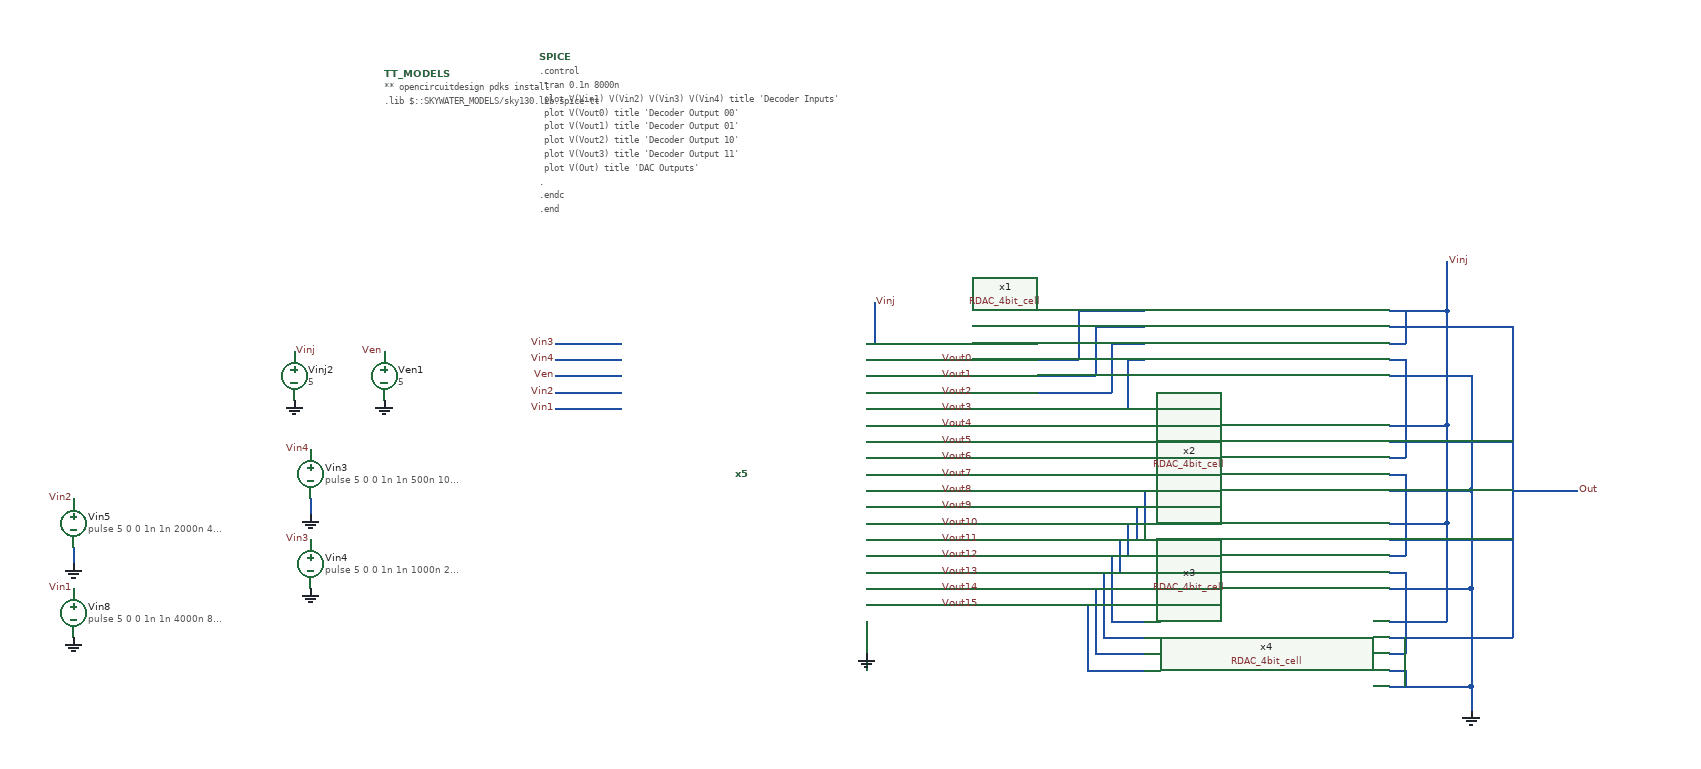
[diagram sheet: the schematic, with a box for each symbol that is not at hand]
v {xschem version=3.4.5 file_version=1.2
}
G {}
K {}
V {}
S {}
E {}
N 340 -380 400 -380 {
lab=Vout4}
N 340 -360 400 -360 {
lab=Vout5}
N 340 -340 400 -340 {
lab=Vout6}
N 340 -320 400 -320 {
lab=Vout7}
N 340 -300 400 -300 {
lab=Vout8}
N 340 -280 400 -280 {
lab=Vout9}
N 400 -520 400 -460 {
lab=Vout0}
N 400 -520 480 -520 {
lab=Vout0}
N 420 -500 480 -500 {
lab=Vout1}
N 420 -500 420 -440 {
lab=Vout1}
N 400 -440 420 -440 {
lab=Vout1}
N 400 -420 440 -420 {
lab=Vout2}
N 440 -480 440 -420 {
lab=Vout2}
N 440 -480 480 -480 {
lab=Vout2}
N 400 -400 460 -400 {
lab=Vout3}
N 460 -460 460 -400 {
lab=Vout3}
N 460 -460 480 -460 {
lab=Vout3}
N 400 -380 480 -380 {
lab=Vout4}
N 400 -360 480 -360 {
lab=Vout5}
N 400 -340 480 -340 {
lab=Vout6}
N 400 -320 480 -320 {
lab=Vout7}
N 400 -300 480 -300 {
lab=Vout8}
N 480 -300 480 -260 {
lab=Vout8}
N 400 -280 470 -280 {
lab=Vout9}
N 470 -280 470 -240 {
lab=Vout9}
N 470 -240 480 -240 {
lab=Vout9}
N 340 -260 460 -260 {
lab=Vout10}
N 460 -260 460 -220 {
lab=Vout10}
N 460 -220 480 -220 {
lab=Vout10}
N 340 -240 450 -240 {
lab=Vout11}
N 450 -240 450 -200 {
lab=Vout11}
N 450 -200 480 -200 {
lab=Vout11}
N 340 -220 440 -220 {
lab=Vout12}
N 440 -220 440 -140 {
lab=Vout12}
N 440 -140 480 -140 {
lab=Vout12}
N 430 -120 480 -120 {
lab=Vout13}
N 430 -200 430 -120 {
lab=Vout13}
N 340 -200 430 -200 {
lab=Vout13}
N 340 -180 420 -180 {
lab=Vout14}
N 420 -180 420 -100 {
lab=Vout14}
N 420 -100 480 -100 {
lab=Vout14}
N 410 -80 480 -80 {
lab=Vout15}
N 410 -160 410 -80 {
lab=Vout15}
N 340 -160 410 -160 {
lab=Vout15}
N 780 -520 850 -520 {
lab=Vinj}
N 850 -520 850 -380 {
lab=Vinj}
N 780 -380 850 -380 {
lab=Vinj}
N 850 -380 850 -260 {
lab=Vinj}
N 780 -260 850 -260 {
lab=Vinj}
N 780 -140 850 -140 {
lab=Vinj}
N 850 -260 850 -140 {
lab=Vinj}
N 780 -60 880 -60 {
lab=GND}
N 880 -180 880 -60 {
lab=GND}
N 780 -180 880 -180 {
lab=GND}
N 780 -300 880 -300 {
lab=GND}
N 780 -440 880 -440 {
lab=GND}
N 880 -300 880 -180 {
lab=GND}
N 880 -440 880 -300 {
lab=GND}
N 780 -500 930 -500 {
lab=Out}
N 930 -500 930 -120 {
lab=Out}
N 780 -120 930 -120 {
lab=Out}
N 780 -240 930 -240 {
lab=Out}
N 780 -360 930 -360 {
lab=Out}
N 930 -300 1010 -300 {
lab=Out}
N 780 -480 800 -480 {
lab=Vinj}
N 800 -520 800 -480 {
lab=Vinj}
N 850 -580 850 -520 {
lab=Vinj}
N 780 -460 800 -460 {
lab=#net1}
N 800 -460 800 -340 {
lab=#net1}
N 780 -340 800 -340 {
lab=#net1}
N 780 -320 800 -320 {
lab=#net2}
N 800 -320 800 -220 {
lab=#net2}
N 780 -220 800 -220 {
lab=#net2}
N 780 -200 800 -200 {
lab=#net3}
N 800 -200 800 -100 {
lab=#net3}
N 780 -100 800 -100 {
lab=#net3}
N 780 -80 800 -80 {
lab=GND}
N 800 -80 800 -60 {
lab=GND}
N 880 -60 880 -30 {
lab=GND}
N -540 -290 -540 -270 {
lab=GND}
N -220 -400 -160 -400 {
lab=Vin1}
N -240 -420 -160 -420 {
lab=Vin2}
N -240 -440 -160 -440 {
lab=Ven}
N -240 -400 -220 -400 {
lab=Vin1}
N -830 -230 -830 -210 {
lab=GND}
N -240 -480 -160 -480 {
lab=Vin3}
N -240 -460 -160 -460 {
lab=Vin4}
N 140 -120 140 -100 {
lab=GND}
N 140 -460 230 -460 {
lab=Vout0}
N 140 -440 230 -440 {
lab=Vout1}
N 140 -420 230 -420 {
lab=Vout2}
N 140 -400 230 -400 {
lab=Vout3}
N 140 -380 230 -380 {
lab=Vout4}
N 140 -360 230 -360 {
lab=Vout5}
N 140 -340 230 -340 {
lab=Vout6}
N 140 -320 230 -320 {
lab=Vout7}
N 140 -300 230 -300 {
lab=Vout8}
N 140 -280 230 -280 {
lab=Vout9}
N 140 -260 230 -260 {
lab=Vout10}
N 140 -240 230 -240 {
lab=Vout11}
N 140 -220 230 -220 {
lab=Vout12}
N 140 -200 230 -200 {
lab=Vout13}
N 140 -180 230 -180 {
lab=Vout14}
N 140 -160 230 -160 {
lab=Vout15}
N 140 -140 140 -120 {
lab=GND}
N 140 -480 150 -480 {
lab=Vinj}
N 150 -530 150 -480 {
lab=Vinj}
N 230 -460 400 -460 {
lab=Vout0}
N 230 -440 400 -440 {
lab=Vout1}
N 230 -420 400 -420 {
lab=Vout2}
N 230 -400 400 -400 {
lab=Vout3}
N 230 -380 340 -380 {
lab=Vout4}
N 230 -360 340 -360 {
lab=Vout5}
N 230 -340 340 -340 {
lab=Vout6}
N 230 -320 340 -320 {
lab=Vout7}
N 230 -300 340 -300 {
lab=Vout8}
N 230 -280 340 -280 {
lab=Vout9}
N 230 -260 340 -260 {
lab=Vout10}
N 230 -240 340 -240 {
lab=Vout11}
N 230 -220 340 -220 {
lab=Vout12}
N 230 -200 340 -200 {
lab=Vout13}
N 230 -180 340 -180 {
lab=Vout14}
N 230 -160 340 -160 {
lab=Vout15}
C {devices/code.sym} -450 -810 0 0 {name=TT_MODELS
only_toplevel=true
format="tcleval( @value )"
value="
** opencircuitdesign pdks install
.lib $::SKYWATER_MODELS/sky130.lib.spice tt

"
spice_ignore=false}
C {code_shown.sym} -260 -830 0 0 {name=SPICE only_toplevel=false value="
.control
	tran 0.1n 8000n
	plot V(Vin1) V(Vin2) V(Vin3) V(Vin4) title 'Decoder Inputs'
	plot V(Vout0) title 'Decoder Output 00'
	plot V(Vout1) title 'Decoder Output 01'
	plot V(Vout2) title 'Decoder Output 10'
	plot V(Vout3) title 'Decoder Output 11'
	plot V(Out) title 'DAC Outputs'
	
.
.endc

.end"}
C {RDAC_4bit_cell.sym} 630 -480 0 0 {name=x1}
C {RDAC_4bit_cell.sym} 630 -340 0 0 {name=x2}
C {RDAC_4bit_cell.sym} 630 -220 0 0 {name=x3}
C {RDAC_4bit_cell.sym} 630 -100 0 0 {name=x4}
C {gnd.sym} 880 -30 0 0 {name=l7 lab=GND}
C {lab_pin.sym} 850 -580 2 0 {name=p1 sig_type=std_logic lab=Vinj}
C {lab_pin.sym} 1010 -300 2 0 {name=p14 sig_type=std_logic lab=Out}
C {vsource.sym} -540 -320 0 0 {name=Vin3 value="pulse 5 0 0 1n 1n 500n 1000n" savecurrent=false}
C {gnd.sym} -540 -270 0 0 {name=l1 lab=GND}
C {vsource.sym} -540 -210 0 0 {name=Vin4 value="pulse 5 0 0 1n 1n 1000n 2000n" savecurrent=false}
C {gnd.sym} -540 -180 0 0 {name=l5 lab=GND}
C {vsource.sym} -560 -440 0 0 {name=Vinj2 value=5 savecurrent=false}
C {gnd.sym} -560 -410 0 0 {name=Vinj3 lab=GND
value=5}
C {lab_pin.sym} -560 -470 2 0 {name=p2 sig_type=std_logic lab=Vinj}
C {lab_pin.sym} -830 -180 0 0 {name=p3 sig_type=std_logic lab=Vin1}
C {lab_pin.sym} -830 -290 0 0 {name=p4 sig_type=std_logic lab=Vin2}
C {vsource.sym} -450 -440 0 0 {name=Ven1 value=5 savecurrent=false}
C {gnd.sym} -450 -410 0 0 {name=l6 lab=GND}
C {lab_pin.sym} -450 -470 0 0 {name=p5 sig_type=std_logic lab=Ven}
C {lab_pin.sym} -240 -400 0 0 {name=p6 sig_type=std_logic lab=Vin1}
C {lab_pin.sym} -240 -420 0 0 {name=p7 sig_type=std_logic lab=Vin2}
C {lab_pin.sym} -240 -440 0 0 {name=p8 sig_type=std_logic lab=Ven}
C {vsource.sym} -830 -260 0 0 {name=Vin5 value="pulse 5 0 0 1n 1n 2000n 4000n" savecurrent=false}
C {gnd.sym} -830 -210 0 0 {name=Vin7 lab=GND}
C {vsource.sym} -830 -150 0 0 {name=Vin8 value="pulse 5 0 0 1n 1n 4000n 8000n" savecurrent=false}
C {gnd.sym} -830 -120 0 0 {name=Vin9 lab=GND}
C {lab_pin.sym} -540 -240 0 0 {name=Vin6 sig_type=std_logic lab=Vin3}
C {lab_pin.sym} -540 -350 0 0 {name=Vin10 sig_type=std_logic lab=Vin4}
C {lab_pin.sym} -240 -480 0 0 {name=Vin11 sig_type=std_logic lab=Vin3}
C {lab_pin.sym} -240 -460 0 0 {name=Vin12 sig_type=std_logic lab=Vin4}
C {lab_pin.sym} 150 -530 2 0 {name=p9 sig_type=std_logic lab=Vinj}
C {gnd.sym} 140 -100 0 0 {name=l2 lab=GND}
C {lab_pin.sym} 230 -460 2 0 {name=p10 sig_type=std_logic lab=Vout0}
C {lab_pin.sym} 230 -440 2 0 {name=p13 sig_type=std_logic lab=Vout1}
C {lab_pin.sym} 230 -420 2 0 {name=p17 sig_type=std_logic lab=Vout2}
C {lab_pin.sym} 230 -400 2 0 {name=p18 sig_type=std_logic lab=Vout3}
C {lab_pin.sym} 230 -380 2 0 {name=p19 sig_type=std_logic lab=Vout4
}
C {lab_pin.sym} 230 -360 2 0 {name=p20 sig_type=std_logic lab=Vout5}
C {lab_pin.sym} 230 -340 2 0 {name=p21 sig_type=std_logic lab=Vout6}
C {lab_pin.sym} 230 -320 2 0 {name=p22 sig_type=std_logic lab=Vout7}
C {lab_pin.sym} 230 -300 2 0 {name=p23 sig_type=std_logic lab=Vout8}
C {lab_pin.sym} 230 -280 2 0 {name=p24 sig_type=std_logic lab=Vout9}
C {lab_pin.sym} 230 -260 2 0 {name=p25 sig_type=std_logic lab=Vout10}
C {lab_pin.sym} 230 -240 2 0 {name=p26 sig_type=std_logic lab=Vout11}
C {lab_pin.sym} 230 -220 2 0 {name=p27 sig_type=std_logic lab=Vout12}
C {lab_pin.sym} 230 -200 2 0 {name=p28 sig_type=std_logic lab=Vout13}
C {lab_pin.sym} 230 -180 2 0 {name=p29 sig_type=std_logic lab=Vout14}
C {lab_pin.sym} 230 -160 2 0 {name=p30 sig_type=std_logic lab=Vout15}
C {sky130_cells/RDAC/Design/sky130_hilas_Vinj_Decode_4to16.sym} -20 -320 0 0 {name=x5}
